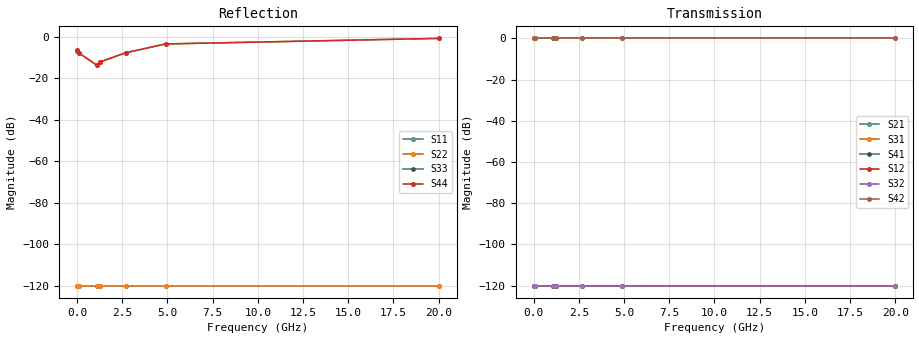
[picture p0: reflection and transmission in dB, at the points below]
! Copyright 2015, Texas Instruments Incorporated. All rights reserved.
! Generated by program util_convert_s2p_term_to_s4p on 06-08-2016 11:14:22
!  1 ----xxxxxxxxxxxxxxxxxx---- 3
!  xxxxxxxxxxxxxxxxxx
!  (Input) xxxxxxxxxxxxxxxxxx  (Output) <--- Termination looking in to TX
!  xxxxxxxxxxxxxxxxxx
!  2 ----xxxxxxxxxxxxxxxxxx---- 4
! FREQ  S11  S12  S13  S14
!  S21  S22  S23  S24
!  S31  S32  S33  S34
!  S41  S42  S43  S44
!  DB  ANG  DB  ANG  DB  ANG  DB  ANG
# HZ S DB R 50.00
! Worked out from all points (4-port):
!   431 points, 1 MHz to 20 GHz, reference 50 ohm
!   strongest paths, dB at 1 MHz, 11.75 MHz, 141.3 MHz, 1.698 GHz, 20 GHz:
!     S42: 0.0, 0.0, 0.0, 0.0, 0.0
!     S31: 0.0, 0.0, 0.0, 0.0, 0.0
!     S43: -5.7, -6.1, -8.8, -21.7, -27.2
!     S41: -120.0, -120.0, -120.0, -120.0, -120.0
!     S32: -120.0, -120.0, -120.0, -120.0, -120.0
!     S21: -120.0, -120.0, -120.0, -120.0, -120.0
!   lowest |S11| = -120.0 dB at 1 MHz (marker M1), VSWR 1.00, Z = 50 + j0 ohm
!   |S11| at or under -10 dB: start of sweep to end of sweep
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1000000  -120.00 0.0  -120.00 0.0  -120.00 0.0  -120.00 0.0
         -120.00 0.0  -120.00 0.0  -120.00 0.0  -120.00 0.0
         0.00 0.0  -120.00 0.0  -6.51 1.1  -5.67 -0.3
         -120.00 0.0  0.00 0.0  -5.67 -0.3  -6.50 1.1
9.77237e7  -120.00 0.0  -120.00 0.0  -120.00 0.0  -120.00 0.0
           -120.00 0.0  -120.00 0.0  -120.00 0.0  -120.00 0.0
           0.00 0.0  -120.00 0.0  -7.61 -34.5  -7.66 -33.8
           -120.00 0.0  0.00 0.0  -7.70 -33.8  -7.66 -34.7
1.09648e9  -120.00 0.0  -120.00 0.0  -120.00 0.0  -120.00 0.0
           -120.00 0.0  -120.00 0.0  -120.00 0.0  -120.00 0.0
           0.00 0.0  -120.00 0.0  -13.70 -94.1  -21.97 -113.6
           -120.00 0.0  0.00 0.0  -21.58 -115.1  -13.51 -95.4
1.25893e9  -120.00 0.0  -120.00 0.0  -120.00 0.0  -120.00 0.0
           -120.00 0.0  -120.00 0.0  -120.00 0.0  -120.00 0.0
           0.00 0.0  -120.00 0.0  -12.16 -94.7  -20.31 -112.7
           -120.00 0.0  0.00 0.0  -20.05 -114.7  -12.03 -96.1
2.69153e9  -120.00 0.0  -120.00 0.0  -120.00 0.0  -120.00 0.0
           -120.00 0.0  -120.00 0.0  -120.00 0.0  -120.00 0.0
           0.00 0.0  -120.00 0.0  -7.63 -105.5  -21.87 176.0
           -120.00 0.0  0.00 0.0  -21.74 177.4  -7.54 -106.0
4.89779e9  -120.00 0.0  -120.00 0.0  -120.00 0.0  -120.00 0.0
           -120.00 0.0  -120.00 0.0  -120.00 0.0  -120.00 0.0
           0.00 0.0  -120.00 0.0  -3.34 -126.4  -22.86 90.2
           -120.00 0.0  0.00 0.0  -22.43 92.6  -3.34 -127.0
2e10  -120.00 0.0  -120.00 0.0  -120.00 0.0  -120.00 0.0
      -120.00 0.0  -120.00 0.0  -120.00 0.0  -120.00 0.0
      0.00 0.0  -120.00 0.0  -0.67 -163.7  -27.32 -30.2
      -120.00 0.0  0.00 0.0  -27.20 -29.7  -0.65 -164.0
